VERSION 5.7 ;
  NOWIREEXTENSIONATPIN ON ;
  DIVIDERCHAR "/" ;
  BUSBITCHARS "[]" ;
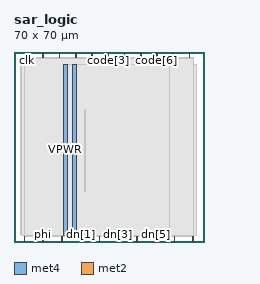
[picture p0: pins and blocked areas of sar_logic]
MACRO sar_logic
  CLASS BLOCK ;
  FOREIGN sar_logic ;
  ORIGIN 0.000 0.000 ;
  SIZE 70.000 BY 70.000 ;
  PIN VGND
    DIRECTION INOUT ;
    USE GROUND ;
    PORT
      LAYER met4 ;
        RECT 21.580 2.480 23.180 65.520 ;
    END
  END VGND
  PIN VPWR
    DIRECTION INOUT ;
    USE POWER ;
    PORT
      LAYER met4 ;
        RECT 18.280 2.480 19.880 65.520 ;
    END
  END VPWR
  PIN clk
    DIRECTION INPUT ;
    USE SIGNAL ;
    ANTENNAGATEAREA 0.852000 ;
    PORT
      LAYER met2 ;
        RECT 4.690 68.000 4.970 70.000 ;
    END
  END clk
  PIN code[0]
    DIRECTION OUTPUT ;
    USE SIGNAL ;
    ANTENNADIFFAREA 3.564000 ;
    PORT
      LAYER met2 ;
        RECT 16.650 68.000 16.930 70.000 ;
    END
  END code[0]
  PIN code[1]
    DIRECTION OUTPUT ;
    USE SIGNAL ;
    ANTENNADIFFAREA 3.564000 ;
    PORT
      LAYER met2 ;
        RECT 22.630 68.000 22.910 70.000 ;
    END
  END code[1]
  PIN code[2]
    DIRECTION OUTPUT ;
    USE SIGNAL ;
    ANTENNADIFFAREA 3.564000 ;
    PORT
      LAYER met2 ;
        RECT 28.610 68.000 28.890 70.000 ;
    END
  END code[2]
  PIN code[3]
    DIRECTION OUTPUT ;
    USE SIGNAL ;
    ANTENNADIFFAREA 3.564000 ;
    PORT
      LAYER met2 ;
        RECT 34.590 68.000 34.870 70.000 ;
    END
  END code[3]
  PIN code[4]
    DIRECTION OUTPUT ;
    USE SIGNAL ;
    ANTENNADIFFAREA 3.564000 ;
    PORT
      LAYER met2 ;
        RECT 40.570 68.000 40.850 70.000 ;
    END
  END code[4]
  PIN code[5]
    DIRECTION OUTPUT ;
    USE SIGNAL ;
    ANTENNADIFFAREA 3.564000 ;
    PORT
      LAYER met2 ;
        RECT 46.550 68.000 46.830 70.000 ;
    END
  END code[5]
  PIN code[6]
    DIRECTION OUTPUT ;
    USE SIGNAL ;
    ANTENNADIFFAREA 3.564000 ;
    PORT
      LAYER met2 ;
        RECT 52.530 68.000 52.810 70.000 ;
    END
  END code[6]
  PIN code[7]
    DIRECTION OUTPUT ;
    USE SIGNAL ;
    ANTENNADIFFAREA 3.564000 ;
    PORT
      LAYER met2 ;
        RECT 58.510 68.000 58.790 70.000 ;
    END
  END code[7]
  PIN comp
    DIRECTION INPUT ;
    USE SIGNAL ;
    ANTENNAGATEAREA 0.159000 ;
    PORT
      LAYER met2 ;
        RECT 3.770 0.000 4.050 2.000 ;
    END
  END comp
  PIN dn[0]
    DIRECTION OUTPUT ;
    USE SIGNAL ;
    ANTENNADIFFAREA 3.564000 ;
    PORT
      LAYER met2 ;
        RECT 17.570 0.000 17.850 2.000 ;
    END
  END dn[0]
  PIN dn[1]
    DIRECTION OUTPUT ;
    USE SIGNAL ;
    ANTENNADIFFAREA 3.564000 ;
    PORT
      LAYER met2 ;
        RECT 24.470 0.000 24.750 2.000 ;
    END
  END dn[1]
  PIN dn[2]
    DIRECTION OUTPUT ;
    USE SIGNAL ;
    ANTENNADIFFAREA 3.564000 ;
    PORT
      LAYER met2 ;
        RECT 31.370 0.000 31.650 2.000 ;
    END
  END dn[2]
  PIN dn[3]
    DIRECTION OUTPUT ;
    USE SIGNAL ;
    ANTENNADIFFAREA 3.564000 ;
    PORT
      LAYER met2 ;
        RECT 38.270 0.000 38.550 2.000 ;
    END
  END dn[3]
  PIN dn[4]
    DIRECTION OUTPUT ;
    USE SIGNAL ;
    ANTENNADIFFAREA 3.564000 ;
    PORT
      LAYER met2 ;
        RECT 45.170 0.000 45.450 2.000 ;
    END
  END dn[4]
  PIN dn[5]
    DIRECTION OUTPUT ;
    USE SIGNAL ;
    ANTENNADIFFAREA 3.564000 ;
    PORT
      LAYER met2 ;
        RECT 52.070 0.000 52.350 2.000 ;
    END
  END dn[5]
  PIN dn[6]
    DIRECTION OUTPUT ;
    USE SIGNAL ;
    ANTENNADIFFAREA 3.564000 ;
    PORT
      LAYER met2 ;
        RECT 58.970 0.000 59.250 2.000 ;
    END
  END dn[6]
  PIN dn[7]
    DIRECTION OUTPUT ;
    USE SIGNAL ;
    ANTENNADIFFAREA 3.564000 ;
    PORT
      LAYER met2 ;
        RECT 65.870 0.000 66.150 2.000 ;
    END
  END dn[7]
  PIN done
    DIRECTION OUTPUT ;
    USE SIGNAL ;
    ANTENNADIFFAREA 3.564000 ;
    PORT
      LAYER met2 ;
        RECT 64.490 68.000 64.770 70.000 ;
    END
  END done
  PIN phi
    DIRECTION OUTPUT ;
    USE SIGNAL ;
    ANTENNADIFFAREA 3.564000 ;
    PORT
      LAYER met2 ;
        RECT 10.670 0.000 10.950 2.000 ;
    END
  END phi
  PIN rst_n
    DIRECTION INPUT ;
    USE SIGNAL ;
    ANTENNAGATEAREA 0.159000 ;
    PORT
      LAYER met2 ;
        RECT 10.670 68.000 10.950 70.000 ;
    END
  END rst_n
  OBS
      LAYER nwell ;
        RECT 2.570 2.635 67.350 65.470 ;
      LAYER li1 ;
        RECT 2.760 2.635 67.160 65.365 ;
      LAYER met1 ;
        RECT 2.760 2.480 67.160 65.520 ;
      LAYER met2 ;
        RECT 3.780 67.720 4.410 68.000 ;
        RECT 5.250 67.720 10.390 68.000 ;
        RECT 11.230 67.720 16.370 68.000 ;
        RECT 17.210 67.720 22.350 68.000 ;
        RECT 23.190 67.720 28.330 68.000 ;
        RECT 29.170 67.720 34.310 68.000 ;
        RECT 35.150 67.720 40.290 68.000 ;
        RECT 41.130 67.720 46.270 68.000 ;
        RECT 47.110 67.720 52.250 68.000 ;
        RECT 53.090 67.720 58.230 68.000 ;
        RECT 59.070 67.720 64.210 68.000 ;
        RECT 65.050 67.720 66.140 68.000 ;
        RECT 3.780 2.280 66.140 67.720 ;
        RECT 4.330 2.000 10.390 2.280 ;
        RECT 11.230 2.000 17.290 2.280 ;
        RECT 18.130 2.000 24.190 2.280 ;
        RECT 25.030 2.000 31.090 2.280 ;
        RECT 31.930 2.000 37.990 2.280 ;
        RECT 38.830 2.000 44.890 2.280 ;
        RECT 45.730 2.000 51.790 2.280 ;
        RECT 52.630 2.000 58.690 2.280 ;
        RECT 59.530 2.000 65.590 2.280 ;
      LAYER met3 ;
        RECT 18.290 2.555 57.435 65.445 ;
      LAYER met4 ;
        RECT 26.055 18.535 26.385 48.785 ;
  END
END sar_logic
END LIBRARY

